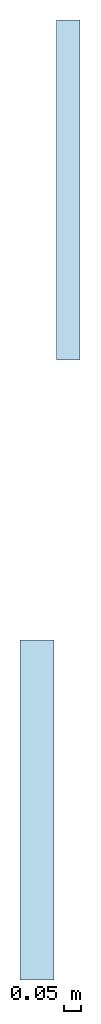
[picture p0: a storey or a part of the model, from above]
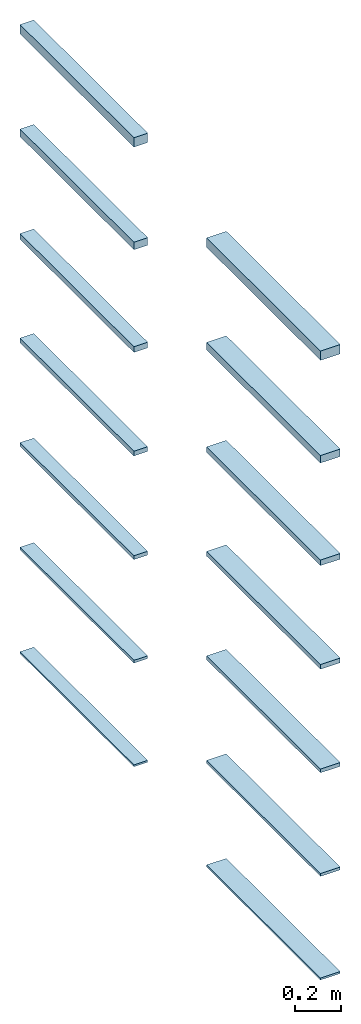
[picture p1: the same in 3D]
Properties of the parts of a building model (IFC2X3)

# File
Description: ViewDefinition [CoordinationView_V2.0]
File name: 0001
Time: 2017-06-13T10:29:56
Written by: The EXPRESS Data Manager Version 5.02.0100.07 : 28 Aug 2013
Made in: 20170223_1515(x64) - Exporter 18.0.0.420 - Alternate UI 18.0.0.420
Comment: STEP Physical File produced by: The EXPRESS Data Manager Version 5.02.0100.07 : 28 Aug 2013 * Module: EDMstepFileFactory/EDMstandAlone * Creation date: Tue Jun 13 10:29:56 2017 * Host: JAVIER * Database: C:\Users\JAVIER~1.DOM\AppData\Local\Temp\{641803A7-FAD0-4DD6-B5D5-F3ACE79C0A6B}\ifc * Database version: 5507 * Database creation date: Tue Jun 13 10:29:56 2017 * Schema: IFC2X3 * Model: DataRepository.ifc * Model creation date: Tue Jun 13 10:29:56 2017 * Header model: DataRepository.ifc_HeaderModel * Header model creation date: Tue Jun 13 10:29:56 2017 * EDMuser: sdai-user * EDMgroup: sdai-group * License ID and type: 5605 : Permanent license. Expiry date: * EDMstepFileFactory options: 020000

# IfcProject, 0001
LongName: Nombre de proyecto; Phase: Estado de proyecto

# IfcSite, Default
RefLatitude: 40, 24, 0, 5493; RefLongitude: -3, -40, -59, -880065; RefElevation: 0 m

# IfcBuilding
Pset_BuildingCommon - NumberOfStoreys: 1

# IfcBuildingStorey, Nivel 1
LongName: Nivel 1; Elevation: 0 m

# IfcSlab: Suelo:Grafipol® TR-0 Tiras_1000x100x10mm, Suelo:Grafipol® TR-0 Tiras_1000x100x10mm:165392
In: Nivel 1
PredefinedType: FLOOR; Classification: C Interiors (Uniformat); Material: VALERO Grafipol® TR-0 Tiras 0.01 m
Pset_SlabCommon - Reference: Grafipol® TR-0 Tiras_1000x100x10mm; IsExternal: no; LoadBearing: no; ThermalTransmittance: 3.3 kg/K/s3; PitchAngle: 0 deg
Pset_ManufacturerTypeInformation - Manufacturer: Grupo Valero - José Manuel Valero, S. L.

# IfcSlab: Suelo:Grafipol® TR-0 Tiras_1000x100x15mm, Suelo:Grafipol® TR-0 Tiras_1000x100x15mm:165750
In: Nivel 1
PredefinedType: FLOOR; Classification: C Interiors (Uniformat); Material: VALERO Grafipol® TR-0 Tiras 0.015 m
Pset_SlabCommon - IsExternal: no; LoadBearing: no; PitchAngle: 0 deg; Reference: Grafipol® TR-0 Tiras_1000x100x15mm; ThermalTransmittance: 2.2 kg/K/s3
Pset_ManufacturerTypeInformation - Manufacturer: Grupo Valero - José Manuel Valero, S. L.

# IfcSlab: Suelo:Grafipol® TR-0 Tiras_1000x100x20mm, Suelo:Grafipol® TR-0 Tiras_1000x100x20mm:165774
In: Nivel 1
PredefinedType: FLOOR; Classification: C Interiors (Uniformat); Material: VALERO Grafipol® TR-0 Tiras 0.02 m
Pset_SlabCommon - IsExternal: no; LoadBearing: no; PitchAngle: 0 deg; Reference: Grafipol® TR-0 Tiras_1000x100x20mm; ThermalTransmittance: 1.65 kg/K/s3
Pset_ManufacturerTypeInformation - Manufacturer: Grupo Valero - José Manuel Valero, S. L.

# IfcSlab: Suelo:Grafipol® TR-0 Tiras_1000x100x25mm, Suelo:Grafipol® TR-0 Tiras_1000x100x25mm:165797
In: Nivel 1
PredefinedType: FLOOR; Classification: C Interiors (Uniformat); Material: VALERO Grafipol® TR-0 Tiras 0.025 m
Pset_SlabCommon - IsExternal: no; LoadBearing: no; PitchAngle: 0 deg; Reference: Grafipol® TR-0 Tiras_1000x100x25mm; ThermalTransmittance: 1.32 kg/K/s3
Pset_ManufacturerTypeInformation - Manufacturer: Grupo Valero - José Manuel Valero, S. L.

# IfcSlab: Suelo:Grafipol® TR-0 Tiras_1000x100x30mm, Suelo:Grafipol® TR-0 Tiras_1000x100x30mm:165804
In: Nivel 1
PredefinedType: FLOOR; Classification: C Interiors (Uniformat); Material: VALERO Grafipol® TR-0 Tiras 0.03 m
Pset_SlabCommon - IsExternal: no; LoadBearing: no; PitchAngle: 0 deg; Reference: Grafipol® TR-0 Tiras_1000x100x30mm; ThermalTransmittance: 1.1 kg/K/s3
Pset_ManufacturerTypeInformation - Manufacturer: Grupo Valero - José Manuel Valero, S. L.

# IfcSlab: Suelo:Grafipol® TR-0 Tiras_1000x100x40mm, Suelo:Grafipol® TR-0 Tiras_1000x100x40mm:165819
In: Nivel 1
PredefinedType: FLOOR; Classification: C Interiors (Uniformat); Material: VALERO Grafipol® TR-0 Tiras 0.04 m
Pset_SlabCommon - IsExternal: no; LoadBearing: no; PitchAngle: 0 deg; Reference: Grafipol® TR-0 Tiras_1000x100x40mm; ThermalTransmittance: 0.825 kg/K/s3
Pset_ManufacturerTypeInformation - Manufacturer: Grupo Valero - José Manuel Valero, S. L.

# IfcSlab: Suelo:Grafipol® TR-0 Tiras_1000x100x50mm, Suelo:Grafipol® TR-0 Tiras_1000x100x50mm:165826
In: Nivel 1
PredefinedType: FLOOR; Classification: C Interiors (Uniformat); Material: VALERO Grafipol® TR-0 Tiras 0.05 m
Pset_SlabCommon - IsExternal: no; LoadBearing: no; PitchAngle: 0 deg; Reference: Grafipol® TR-0 Tiras_1000x100x50mm; ThermalTransmittance: 0.66 kg/K/s3
Pset_ManufacturerTypeInformation - Manufacturer: Grupo Valero - José Manuel Valero, S. L.

# IfcSlab: Suelo:Grafipol® TR-0 Tiras_1000x70x10mm, Suelo:Grafipol® TR-0 Tiras_1000x70x10mm:166631
In: Nivel 1
PredefinedType: FLOOR; Classification: C Interiors (Uniformat); Material: VALERO Grafipol® TR-0 Tiras 0.01 m
Pset_SlabCommon - IsExternal: no; LoadBearing: no; ThermalTransmittance: 3.3 kg/K/s3; PitchAngle: 0 deg; Reference: Grafipol® TR-0 Tiras_1000x70x10mm
Pset_ManufacturerTypeInformation - Manufacturer: Grupo Valero - José Manuel Valero, S. L.

# IfcSlab: Suelo:Grafipol® TR-0 Tiras_1000x70x15mm, Suelo:Grafipol® TR-0 Tiras_1000x70x15mm:166637
In: Nivel 1
PredefinedType: FLOOR; Classification: C Interiors (Uniformat); Material: VALERO Grafipol® TR-0 Tiras 0.015 m
Pset_SlabCommon - IsExternal: no; LoadBearing: no; PitchAngle: 0 deg; ThermalTransmittance: 2.2 kg/K/s3; Reference: Grafipol® TR-0 Tiras_1000x70x15mm
Pset_ManufacturerTypeInformation - Manufacturer: Grupo Valero - José Manuel Valero, S. L.

# IfcSlab: Suelo:Grafipol® TR-0 Tiras_1000x70x20mm, Suelo:Grafipol® TR-0 Tiras_1000x70x20mm:166643
In: Nivel 1
PredefinedType: FLOOR; Classification: C Interiors (Uniformat); Material: VALERO Grafipol® TR-0 Tiras 0.02 m
Pset_SlabCommon - IsExternal: no; LoadBearing: no; PitchAngle: 0 deg; ThermalTransmittance: 1.65 kg/K/s3; Reference: Grafipol® TR-0 Tiras_1000x70x20mm
Pset_ManufacturerTypeInformation - Manufacturer: Grupo Valero - José Manuel Valero, S. L.

# IfcSlab: Suelo:Grafipol® TR-0 Tiras_1000x70x25mm, Suelo:Grafipol® TR-0 Tiras_1000x70x25mm:166649
In: Nivel 1
PredefinedType: FLOOR; Classification: C Interiors (Uniformat); Material: VALERO Grafipol® TR-0 Tiras 0.025 m
Pset_SlabCommon - IsExternal: no; LoadBearing: no; PitchAngle: 0 deg; Reference: Grafipol® TR-0 Tiras_1000x70x25mm; ThermalTransmittance: 1.32 kg/K/s3
Pset_ManufacturerTypeInformation - Manufacturer: Grupo Valero - José Manuel Valero, S. L.

# IfcSlab: Suelo:Grafipol® TR-0 Tiras_1000x70x30mm, Suelo:Grafipol® TR-0 Tiras_1000x70x30mm:166655
In: Nivel 1
PredefinedType: FLOOR; Classification: C Interiors (Uniformat); Material: VALERO Grafipol® TR-0 Tiras 0.03 m
Pset_SlabCommon - IsExternal: no; LoadBearing: no; PitchAngle: 0 deg; ThermalTransmittance: 1.1 kg/K/s3; Reference: Grafipol® TR-0 Tiras_1000x70x30mm
Pset_ManufacturerTypeInformation - Manufacturer: Grupo Valero - José Manuel Valero, S. L.

# IfcSlab: Suelo:Grafipol® TR-0 Tiras_1000x70x40mm, Suelo:Grafipol® TR-0 Tiras_1000x70x40mm:166661
In: Nivel 1
PredefinedType: FLOOR; Classification: C Interiors (Uniformat); Material: VALERO Grafipol® TR-0 Tiras 0.04 m
Pset_SlabCommon - IsExternal: no; LoadBearing: no; PitchAngle: 0 deg; Reference: Grafipol® TR-0 Tiras_1000x70x40mm; ThermalTransmittance: 0.825 kg/K/s3
Pset_ManufacturerTypeInformation - Manufacturer: Grupo Valero - José Manuel Valero, S. L.

# IfcSlab: Suelo:Grafipol® TR-0 Tiras_1000x70x50mm, Suelo:Grafipol® TR-0 Tiras_1000x70x50mm:166667
In: Nivel 1
PredefinedType: FLOOR; Classification: C Interiors (Uniformat); Material: VALERO Grafipol® TR-0 Tiras 0.05 m
Pset_SlabCommon - IsExternal: no; LoadBearing: no; PitchAngle: 0 deg; Reference: Grafipol® TR-0 Tiras_1000x70x50mm; ThermalTransmittance: 0.66 kg/K/s3
Pset_ManufacturerTypeInformation - Manufacturer: Grupo Valero - José Manuel Valero, S. L.
